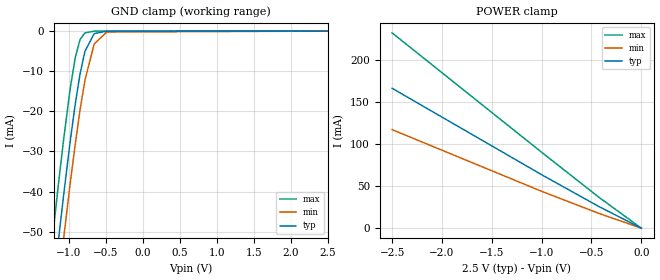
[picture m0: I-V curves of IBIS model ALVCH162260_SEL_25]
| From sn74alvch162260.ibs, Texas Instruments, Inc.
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[Model]   ALVCH162260_SEL_25
Model_type  Input
Vinl=0.7
Vinh=1.7
| variable   typ   min   max
C_comp   27.18pF   21.90pF   32.67pF
[Temperature Range]   40   100   -40
| Ambient temperature   25   85   -40
[Voltage range]   2.5   2.3   2.7
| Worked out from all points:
|   GND clamp passes 1 mA (typ) near -0.68 V on its own axis
|   POWER clamp passes 1 mA (typ) near -0.02 V on its own axis
[GND Clamp]
| ALVCH162260_SEL_25
|   Voltage   I(typ)   I(min)   I(max)
-2.5V     -300mA     -309.4mA   -288.3mA
-1.22V    -65.92mA   -76.78mA   -51.96mA
-1.15V    -54.2mA    -65.07mA   -40.19mA
-1.125V   -50.1mA    -60.96mA   -36.1mA
-1.07V    -41.27mA   -52.08mA   -27.39mA
-980mV    -27.63mA   -38.14mA   -14.46mA
-910mV    -18.08mA   -28.05mA   -6.523mA
-845mV    -10.58mA   -19.54mA   -2.069mA
-780mV    -5.041mA   -12.24mA   -440.8uA
-655mV    -630uA     -3.209mA   -15.41uA
-485mV    -21.18uA   -229.3uA   -148.8nA
2.5V      1.112nA    1.808uA    4.19pA
[POWER Clamp]
| ALVCH162260_SEL_25
|   Voltage   I(typ)   I(min)   I(max)
-2.5V     166mA      116.9mA    231.7mA
-990mV    62.77mA    43.26mA    89.14mA
-425mV    25.67mA    17.51mA    36.62mA
-31.15fV  211.9pA    285.8pA    93.4pA
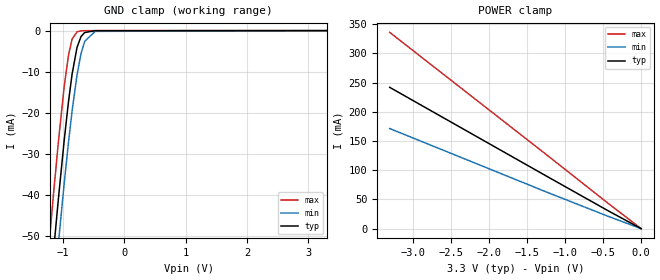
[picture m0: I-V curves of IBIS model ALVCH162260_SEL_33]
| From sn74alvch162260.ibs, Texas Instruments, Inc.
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[Model]   ALVCH162260_SEL_33
Model_type  Input
Vinl=0.8
Vinh=2.0
| variable   typ   min   max
C_comp   28.03pF   21.19pF   32.72pF
[Temperature Range]   40   100   -40
| Ambient temperature   25   85   -40
[Voltage range]   3.3   3   3.6
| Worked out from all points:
|   GND clamp passes 1 mA (typ) near -0.68 V on its own axis
|   POWER clamp passes 1 mA (typ) near -0.01 V on its own axis
[GND Clamp]
| ALVCH162260_SEL_33
|   Voltage   I(typ)   I(min)   I(max)
-3.3V     -451.4mA   -460.2mA   -440.6mA
-1.225V   -66.77mA   -77.63mA   -52.81mA
-1.14V    -52.55mA   -63.42mA   -38.55mA
-1.07V    -41.27mA   -52.08mA   -27.39mA
-975mV    -26.91mA   -37.4mA    -13.81mA
-905mV    -17.45mA   -27.36mA   -6.068mA
-845mV    -10.58mA   -19.54mA   -2.069mA
-765mV    -4.1mA     -10.78mA   -298.6uA
-700mV    -1.444mA   -5.604mA   -52.39uA
-640mV    -472.1uA   -2.617mA   -10.24uA
-470mV    -15.62uA   -178.3uA   -98.79nA
3.3V      1.114nA    9.952uA    5.63pA
[POWER Clamp]
| ALVCH162260_SEL_33
|   Voltage   I(typ)   I(min)   I(max)
-3.3V     241.9mA    171.4mA    336mA
-1.23V    89.02mA    62.04mA    125.3mA
-435mV    30.74mA    21.22mA    43.48mA
-48.03fV  3.196nA    1.217nA    4.97nA
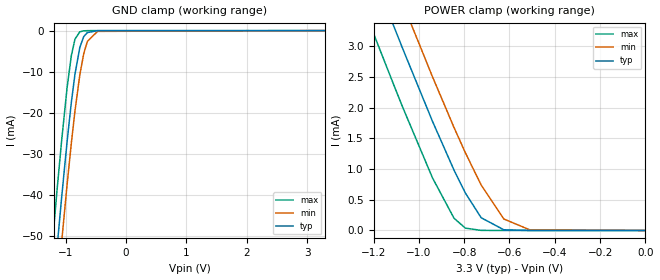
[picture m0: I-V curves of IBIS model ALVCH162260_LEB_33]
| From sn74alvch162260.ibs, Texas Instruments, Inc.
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[Model]   ALVCH162260_LEB_33
Model_type  Input
Vinl=0.8
Vinh=2.0
| variable   typ   min   max
C_comp   1.76pF   1.54pF   2.35pF
[Temperature Range]   40   100   -40
| Ambient temperature   25   85   -40
[Voltage range]   3.3   3   3.6
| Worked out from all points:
|   GND clamp passes 1 mA (typ) near -0.68 V on its own axis
|   POWER clamp passes 1 mA (typ) near -0.85 V on its own axis
[GND Clamp]
| ALVCH162260_LEB_33
|   Voltage   I(typ)   I(min)   I(max)
-3.3V     -451.4mA   -460.2mA   -440.6mA
-1.225V   -66.77mA   -77.63mA   -52.81mA
-1.14V    -52.55mA   -63.42mA   -38.55mA
-1.07V    -41.27mA   -52.08mA   -27.39mA
-975mV    -26.91mA   -37.4mA    -13.81mA
-905mV    -17.45mA   -27.36mA   -6.068mA
-845mV    -10.58mA   -19.54mA   -2.069mA
-765mV    -4.1mA     -10.78mA   -298.6uA
-700mV    -1.444mA   -5.604mA   -52.39uA
-640mV    -472.1uA   -2.617mA   -10.24uA
-470mV    -15.62uA   -178.3uA   -98.79nA
3.3V      1.114nA    9.952uA    5.63pA
[POWER Clamp]
| ALVCH162260_LEB_33
|   Voltage   I(typ)   I(min)   I(max)
-3.3V     24.83mA    25.52mA    23.96mA
-1.275V   4.872mA    5.61mA     3.918mA
-1.185V   4.018mA    4.758mA    3.062mA
-1.105V   3.269mA    4.008mA    2.314mA
-1.07V    2.945mA    3.683mA    1.992mA
-940mV    1.776mA    2.501mA    856.4uA
-845mV    982.9uA    1.676mA    200.1uA
-795mV    611.2uA    1.266mA    38.41uA
-725mV    207uA      738.7uA    1.527uA
-625mV    11.21uA    186.8uA    11.91nA
-510mV    181.6nA    9.688uA    52.91pA
-48.03fV  6.303pA    7.801pA    6.677pA
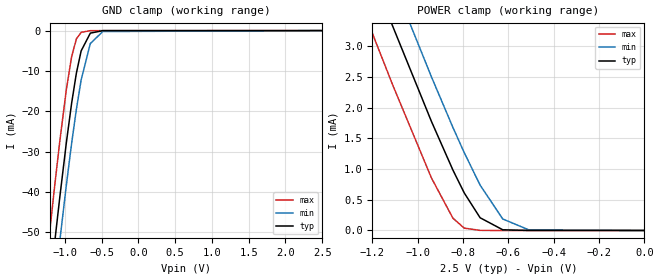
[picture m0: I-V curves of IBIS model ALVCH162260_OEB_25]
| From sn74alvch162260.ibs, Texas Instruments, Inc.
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[Model]   ALVCH162260_OEB_25
Model_type  Input
Vinl=0.7
Vinh=1.7
| variable   typ   min   max
C_comp   1.70pF   1.55pF   2.09pF
[Temperature Range]   40   100   -40
| Ambient temperature   25   85   -40
[Voltage range]   2.5   2.3   2.7
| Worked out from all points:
|   GND clamp passes 1 mA (typ) near -0.68 V on its own axis
|   POWER clamp passes 1 mA (typ) near -0.85 V on its own axis
[GND Clamp]
| ALVCH162260_OEB_25
|   Voltage   I(typ)   I(min)   I(max)
-2.5V     -300mA     -309.4mA   -288.3mA
-1.22V    -65.92mA   -76.78mA   -51.96mA
-1.15V    -54.2mA    -65.07mA   -40.19mA
-1.125V   -50.1mA    -60.96mA   -36.1mA
-1.07V    -41.27mA   -52.08mA   -27.39mA
-980mV    -27.63mA   -38.14mA   -14.46mA
-910mV    -18.08mA   -28.05mA   -6.523mA
-845mV    -10.58mA   -19.54mA   -2.069mA
-780mV    -5.041mA   -12.24mA   -440.8uA
-655mV    -630uA     -3.209mA   -15.41uA
-485mV    -21.18uA   -229.3uA   -148.8nA
2.5V      1.112nA    1.808uA    4.19pA
[POWER Clamp]
| ALVCH162260_OEB_25
|   Voltage   I(typ)   I(min)   I(max)
-2.5V     16.88mA    17.58mA    15.98mA
-1.3V     5.111mA    5.849mA    4.158mA
-1.255V   4.681mA    5.42mA     3.727mA
-1.18V    3.971mA    4.711mA    3.015mA
-1.11V    3.316mA    4.055mA    2.36mA
-940mV    1.776mA    2.501mA    856.4uA
-845mV    982.9uA    1.676mA    200.1uA
-795mV    611.2uA    1.266mA    38.41uA
-725mV    207uA      738.7uA    1.527uA
-625mV    11.21uA    186.8uA    11.91nA
-510mV    181.6nA    9.688uA    51.12pA
-31.15fV  4.712pA    6.41pA     4.886pA
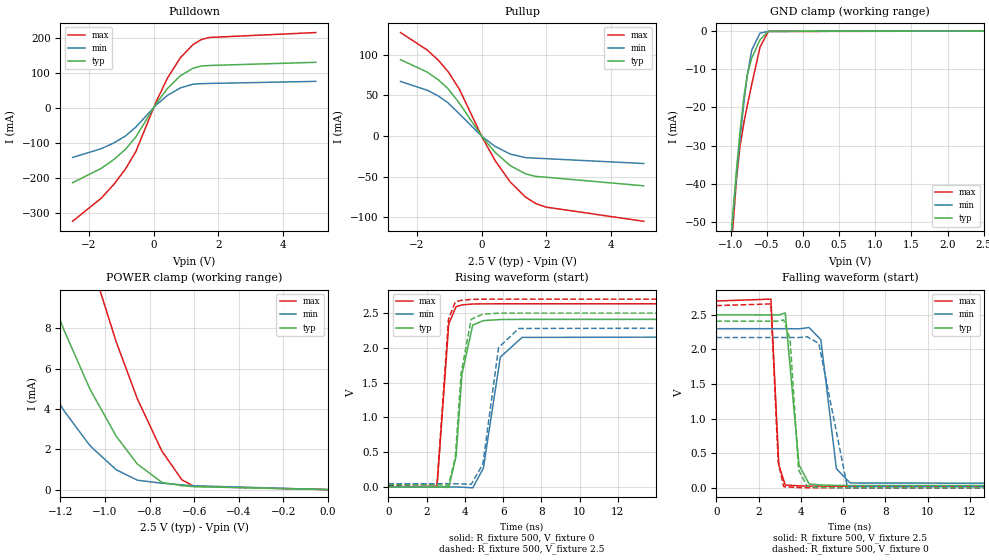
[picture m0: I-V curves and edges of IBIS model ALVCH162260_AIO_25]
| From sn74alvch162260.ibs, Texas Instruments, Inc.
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[Model]   ALVCH162260_AIO_25
Model_type  I/O
Vinl=0.7
Vinh=1.7
Enable   Active-Low
Vref =   0
Rref =   500
Cref =   30p
Vmeas =   1.25
| variable   typ   min   max
C_comp   8.61pF   7.54pF   9.59pF
| C_pullup   9.77pF   8.12pF   10.70pF
| C_pulldown   13.11pF   10.21pF   16.92pF
| C_tri-state   8.61pF   7.54pF   9.59pF
[Temperature Range]   40   100   -40
| Ambient temperature   25   85   -40
[Voltage range]   2.5   2.3   2.7
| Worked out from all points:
|   slope of the pulldown table from 0 to 0.375 V, typ, clamps not added: 7.66 ohm
|   slope of the pullup table from 0 to 0.375 V, typ, clamps not added: 20.6 ohm
|   GND clamp passes 1 mA (typ) near -0.55 V on its own axis
|   POWER clamp passes 1 mA (typ) near -0.83 V on its own axis
|   rising waveform, R_fixture 500, V_fixture 0: 20-80 % time 414ps typ, 652ps min, 290ps max; typ from 0 V to 2.41 V
|   falling waveform, R_fixture 500, V_fixture 2.5: 20-80 % time 280ps typ, 461ps min, 178ps max; typ from 2.5 V to 0.034 V
|   rising waveform, R_fixture 500, V_fixture 2.5: 20-80 % time 397ps typ, 592ps min, 281ps max; typ from 0.034 V to 2.5 V
|   falling waveform, R_fixture 500, V_fixture 0: 20-80 % time 268ps typ, 431ps min, 172ps max; typ from 2.41 V to 0 V
[GND Clamp]
| ALVCH162260_AIO_25
|   Voltage   I(typ)   I(min)   I(max)
-2.5V     -468.2mA   -428.5mA   -529.7mA
-1.095V   -77.4mA    -75.37mA   -83.81mA
-1.08V    -73.67mA   -71.99mA   -79.57mA
-1.06V    -68.73mA   -67.51mA   -73.98mA
-920mV    -36.21mA   -37.68mA   -38.65mA
-870mV    -26.07mA   -27.97mA   -29.9mA
-815mV    -16.78mA   -18.28mA   -23.65mA
-770mV    -11.4mA    -11.53mA   -19.45mA
-710mV    -7.125mA   -5.047mA   -14.04mA
-595mV    -2.318mA   -568.8uA   -4.241mA
-480mV    -118.2uA   -124.4uA   -159.8uA
2.5V      87.96pA    20.8uA     -42.68uA
[POWER Clamp]
| ALVCH162260_AIO_25
|   Voltage   I(typ)   I(min)   I(max)
-2.5V     63.25mA    42.74mA    94.06mA
-1.535V   19.36mA    11.44mA    33.3mA
-1.295V   11.13mA    5.943mA    21.18mA
-1.185V   7.93mA     3.923mA    16.24mA
-1.075V   5.165mA    2.287mA    11.76mA
-1.06V    4.826mA    2.097mA    11.19mA
-950mV    2.649mA    983.8uA    7.329mA
-855mV    1.266mA    465.9uA    4.501mA
-745mV    358.2uA    317uA      1.91mA
-655mV    193uA      236.3uA    483.8uA
-600mV    145.9uA    190.2uA    159.3uA
-31.15fV  87.96pA    322.3pA    50.89pA
[Pulldown]
| ALVCH162260_AIO_25
|   Voltage   I(typ)   I(min)   I(max)
-2.5V     -214.5mA   -142.4mA   -324.7mA
-1.625V   -174.1mA   -117.7mA   -259.4mA
-1.225V   -148.2mA   -100.9mA   -219.1mA
-870mV    -119.2mA   -81.23mA   -175.5mA
-550mV    -84.06mA   -55.7mA    -125.8mA
75mV      10.83mA    7.022mA    16.48mA
430mV     55.09mA    35.04mA    84.84mA
825mV     90.83mA    56.18mA    142.3mA
1.215V    112.2mA    66.71mA    179.9mA
1.465V    118.6mA    68.28mA    193.9mA
1.715V    120.1mA    68.86mA    200.1mA
5V        129.2mA    74.77mA    214.1mA
[Pullup]
| ALVCH162260_AIO_25
|   Voltage   I(typ)   I(min)   I(max)
-2.5V     93.89mA    67.09mA    127.2mA
-1.675V   78.56mA    56.27mA    105.7mA
-1.335V   69.15mA    49.28mA    93.27mA
-1.035V   58.23mA    40.89mA    79.35mA
-685mV    40.38mA    27.22mA    57.59mA
15mV      -812.9uA   -531.7uA   -1.2mA
420mV     -20.15mA   -12.8mA    -30.36mA
885mV     -36.42mA   -22.17mA   -56.52mA
1.355V    -46.47mA   -26.53mA   -75.01mA
1.67V     -49.6mA    -27.19mA   -82.95mA
1.985V    -50.63mA   -27.82mA   -87.32mA
5V        -61.14mA   -33.76mA   -104.8mA
[Ramp]
| ALVCH162260_AIO_25
| variable   typ   min   max
dV/dt_r   1.45/4.21E-10   1.31/6.60E-10   1.59/3.04E-10
dV/dt_f   1.50/2.90E-10   1.37/4.71E-10   1.63/1.89E-10
R_load = 500
[Rising Waveform]
| ALVCH162260_AIO_25
R_fixture =   500
C_fixture =   0
L_fixture =   0
V_fixture =   0
V_fixture_min = 0
V_fixture_max = 0
|   Time   V(typ)   V(min)   V(max)
0s        360.6pV    1.412nV    255.5pV
2.545ns   1.401mV    -88.12uV   11.99mV
3.16ns    -4.821mV   1.034mV    2.347V
3.54ns    440.7mV    703.7uV    2.591V
3.85ns    1.624V     -1.002mV   2.617V
4.415ns   2.327V     -11.56mV   2.63V
4.97ns    2.391V     271.5mV    2.632V
5.855ns   2.407V     1.867V     2.633V
6.995ns   2.409V     2.15V      2.633V
50ns      2.409V     2.172V     2.633V
[Falling Waveform]
| ALVCH162260_AIO_25
R_fixture =   500
C_fixture =   0
L_fixture =   0
V_fixture =   2.5
V_fixture_min = 2.3
V_fixture_max = 2.7
|   Time   V(typ)   V(min)   V(max)
0s        2.5V       2.3V       2.7V
2.585ns   2.499V     2.3V       2.727V
2.96ns    2.498V     2.3V       326.9mV
3.265ns   2.528V     2.3V       40.44mV
3.915ns   331mV      2.298V     29.13mV
4.395ns   55.32mV    2.316V     25.29mV
4.95ns    41.36mV    2.139V     24.37mV
5.685ns   35.35mV    276.9mV    24.06mV
6.33ns    34.11mV    71.3mV     23.99mV
50ns      33.66mV    47.56mV    23.96mV
[Rising Waveform]
| ALVCH162260_AIO_25
R_fixture =   500
C_fixture =   0
L_fixture =   0
V_fixture =   2.5
V_fixture_min = 2.3
V_fixture_max = 2.7
|   Time   V(typ)   V(min)   V(max)
0s        33.65mV    47.56mV    23.96mV
2.545ns   34.63mV    47.55mV    37.19mV
3.145ns   26.99mV    48.28mV    2.411V
3.5ns     423.5mV    47.34mV    2.658V
3.805ns   1.63V      45.73mV    2.683V
4.33ns    2.41V      39.05mV    2.696V
4.94ns    2.484V     327.2mV    2.699V
5.765ns   2.498V     2.005V     2.7V
6.82ns    2.5V       2.278V     2.7V
50ns      2.5V       2.3V       2.7V
[Falling Waveform]
| ALVCH162260_AIO_25
R_fixture =   500
C_fixture =   0
L_fixture =   0
V_fixture =   0
V_fixture_min = 0
V_fixture_max = 0
|   Time   V(typ)   V(min)   V(max)
0s        2.409V     2.172V     2.633V
2.585ns   2.408V     2.172V     2.658V
2.93ns    2.408V     2.173V     377.1mV
3.19ns    2.427V     2.172V     17.32mV
3.495ns   2.143V     2.172V     10.92mV
3.895ns   261mV      2.172V     4.629mV
4.305ns   20.19mV    2.183V     1.361mV
4.855ns   7.087mV    2.086V     399.7uV
6.2ns     389.6uV    19.58mV    34.94uV
50ns      231.3nV    435.8nV    114.6nV
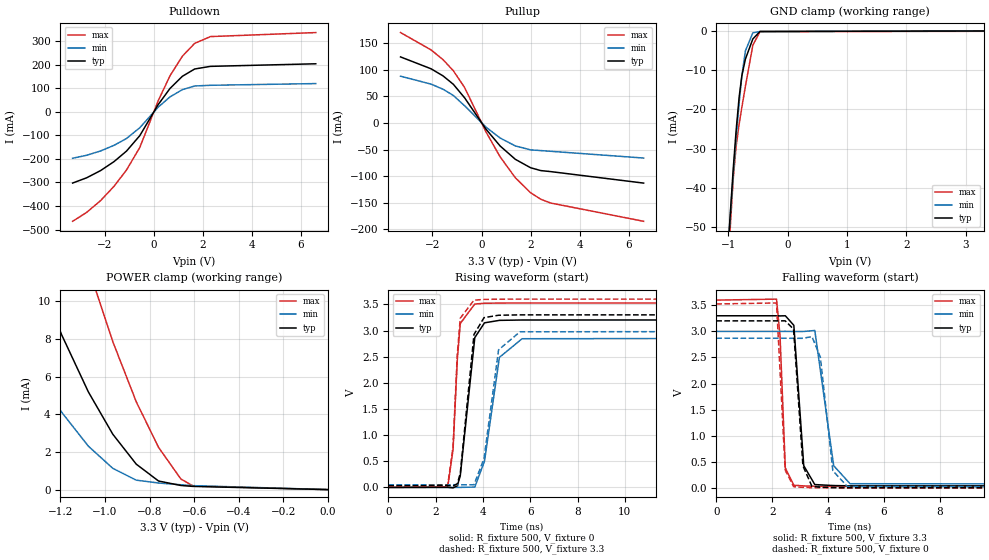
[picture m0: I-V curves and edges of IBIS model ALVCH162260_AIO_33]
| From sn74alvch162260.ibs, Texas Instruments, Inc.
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[Model]   ALVCH162260_AIO_33
Model_type  I/O
Vinl=0.8
Vinh=2.0
Enable   Active-Low
Vref =   0
Rref =   500
Cref =   50p
Vmeas =   1.5
| variable   typ   min   max
C_comp   4.5pF   NA   NA
| C_pullup   9.52pF   7.89pF   10.49pF
| C_pulldown   12.76pF   10.08pF   16.26pF
| C_tri-state   8.39pF   7.23pF   9.52pF
[Temperature Range]   40   100   -40
| Ambient temperature   25   85   -40
[Voltage range]   3.3   3   3.6
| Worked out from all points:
|   slope of the pulldown table from 0 to 0.495 V, typ, clamps not added: 6.36 ohm
|   slope of the pullup table from 0 to 0.495 V, typ, clamps not added: 16.5 ohm
|   GND clamp passes 1 mA (typ) near -0.55 V on its own axis
|   POWER clamp passes 1 mA (typ) near -0.83 V on its own axis
|   rising waveform, R_fixture 500, V_fixture 0: 20-80 % time 343ps typ, 493ps min, 239ps max; typ from 0 V to 3.2 V
|   falling waveform, R_fixture 500, V_fixture 3.3: 20-80 % time 216ps typ, 328ps min, 142ps max; typ from 3.3 V to 0.037 V
|   rising waveform, R_fixture 500, V_fixture 3.3: 20-80 % time 335ps typ, 468ps min, 236ps max; typ from 0.037 V to 3.3 V
|   falling waveform, R_fixture 500, V_fixture 0: 20-80 % time 204ps typ, 312ps min, 139ps max; typ from 3.2 V to 0 V
[GND Clamp]
| ALVCH162260_AIO_33
|   Voltage   I(typ)   I(min)   I(max)
-3.3V     -702.5mA   -640.1mA   -797.1mA
-1.09V    -76.2mA    -74.27mA   -82.45mA
-1.07V    -71.24mA   -69.78mA   -76.83mA
-1.05V    -66.34mA   -65.33mA   -71.28mA
-915mV    -35.19mA   -36.71mA   -37.68mA
-865mV    -25.17mA   -27.07mA   -29.27mA
-815mV    -16.82mA   -18.31mA   -23.7mA
-770mV    -11.44mA   -11.56mA   -19.5mA
-710mV    -7.159mA   -5.072mA   -14.09mA
-585mV    -2.033mA   -471.5uA   -3.632mA
-465mV    -132uA     -129.7uA   -181.2uA
3.3V      119.8pA    41.6uA     -79.23uA
[POWER Clamp]
| ALVCH162260_AIO_33
|   Voltage   I(typ)   I(min)   I(max)
-3.3V     106.7mA    74.61mA    152.6mA
-1.545V   19.78mA    11.73mA    33.9mA
-1.42V    15.27mA    8.669mA    27.34mA
-1.32V    11.95mA    6.481mA    22.41mA
-1.195V   8.24mA     4.119mA    16.72mA
-1.075V   5.198mA    2.312mA    11.8mA
-965mV    2.942mA    1.129mA    7.86mA
-860mV    1.354mA    503uA      4.672mA
-760mV    457.3uA    350.6uA    2.248mA
-660mV    219.9uA    257.6uA    567.3uA
-605mV    170.3uA    210.1uA    193.1uA
-48.03fV  119.8pA    365.6pA    68.2pA
[Pulldown]
| ALVCH162260_AIO_33
|   Voltage   I(typ)   I(min)   I(max)
-3.3V     -302.4mA   -196.9mA   -465.1mA
-2.73V    -280.1mA   -184.3mA   -427.4mA
-2.16V    -249.3mA   -165.8mA   -377mA
-1.61V    -210.9mA   -141.8mA   -315.8mA
-1.105V   -166.3mA   -112.9mA   -246.6mA
-565mV    -100.8mA   -67.07mA   -151.3mA
185mV     31.43mA    20.51mA    47.78mA
665mV     100mA      64.12mA    153.8mA
1.17V     151.9mA    95.01mA    237.4mA
1.67V     182.8mA    110.5mA    291.9mA
2.31V     194mA      113.5mA    320.7mA
6.6V      205mA      120.8mA    337.8mA
[Pullup]
| ALVCH162260_AIO_33
|   Voltage   I(typ)   I(min)   I(max)
-3.3V     124.6mA    88.26mA    170.5mA
-2.055V   102.2mA    73.29mA    137.8mA
-1.565V   88.69mA    63.61mA    119.2mA
-1.15V    73.01mA    51.93mA    98.57mA
-690mV    47.45mA    32.47mA    66.81mA
180mV     -11.59mA   -7.766mA   -16.76mA
755mV     -43.3mA    -28.29mA   -63.76mA
1.375V    -68.47mA   -43.2mA    -103.3mA
1.995V    -84.31mA   -50.62mA   -131.4mA
2.405V    -89.66mA   -51.96mA   -143.6mA
2.81V     -91.58mA   -53.32mA   -150.8mA
6.6V      -113.3mA   -66.05mA   -185.3mA
[Ramp]
| ALVCH162260_AIO_33
| variable   typ   min   max
dV/dt_r   1.93/3.53E-10   1.73/5.04E-10   2.12/2.40E-10
dV/dt_f   1.98/2.23E-10   1.79/3.39E-10   2.16/1.46E-10
R_load = 500
[Rising Waveform]
| ALVCH162260_AIO_33
R_fixture =   500
C_fixture =   0
L_fixture =   0
V_fixture =   0
V_fixture_min = 0
V_fixture_max = 0
|   Time   V(typ)   V(min)   V(max)
0s        395.9pV    1.295nV    284.2pV
2.51ns    2.238mV    69uV       12.47mV
2.735ns   -7.841mV   1.226mV    723.5mV
2.915ns   30.69mV    1.806mV    2.441V
3.04ns    221mV      1.18mV     3.134V
3.655ns   2.865V     7.182mV    3.506V
4.065ns   3.147V     499.9mV    3.521V
4.695ns   3.194V     2.487V     3.525V
5.655ns   3.201V     2.843V     3.526V
50ns      3.202V     2.869V     3.526V
[Falling Waveform]
| ALVCH162260_AIO_33
R_fixture =   500
C_fixture =   0
L_fixture =   0
V_fixture =   3.3
V_fixture_min = 3
V_fixture_max = 3.6
|   Time   V(typ)   V(min)   V(max)
0s        3.3V       3V         3.6V
2.155ns   3.3V       3V         3.619V
2.28ns    3.297V     3V         2.925V
2.47ns    3.3V       3.001V     382.4mV
2.775ns   3.117V     2.998V     50.91mV
3.13ns    425mV      2.999V     37.26mV
3.525ns   63.14mV    3.018V     29.87mV
4.2ns     44.17mV    425.6mV    27.32mV
4.785ns   38.61mV    79.66mV    26.89mV
50ns      37.01mV    51.2mV     26.69mV
[Rising Waveform]
| ALVCH162260_AIO_33
R_fixture =   500
C_fixture =   0
L_fixture =   0
V_fixture =   3.3
V_fixture_min = 3
V_fixture_max = 3.6
|   Time   V(typ)   V(min)   V(max)
0s        37.01mV    51.2mV     26.69mV
2.51ns    38.7mV     51.35mV    40.04mV
2.735ns   28.75mV    52.26mV    781.9mV
2.915ns   69.82mV    52.38mV    2.544V
3.04ns    267.3mV    51.42mV    3.236V
3.62ns    2.924V     51.11mV    3.58V
4.045ns   3.246V     553.5mV    3.595V
4.66ns    3.292V     2.63V      3.599V
5.565ns   3.299V     2.975V     3.6V
50ns      3.3V       3V         3.6V
[Falling Waveform]
| ALVCH162260_AIO_33
R_fixture =   500
C_fixture =   0
L_fixture =   0
V_fixture =   0
V_fixture_min = 0
V_fixture_max = 0
|   Time   V(typ)   V(min)   V(max)
0s        3.202V     2.869V     3.526V
2.155ns   3.202V     2.869V     3.545V
2.465ns   3.203V     2.869V     340.7mV
2.765ns   3.044V     2.867V     22.43mV
3.1ns     422mV      2.868V     10.2mV
3.425ns   25.36mV    2.9V       3.796mV
3.725ns   14.88mV    2.505V     1.536mV
4.17ns    6.313mV    328.1mV    578uV
4.69ns    1.564mV    25.95mV    207.8uV
50ns      175.1nV    317.2nV    87.06nV
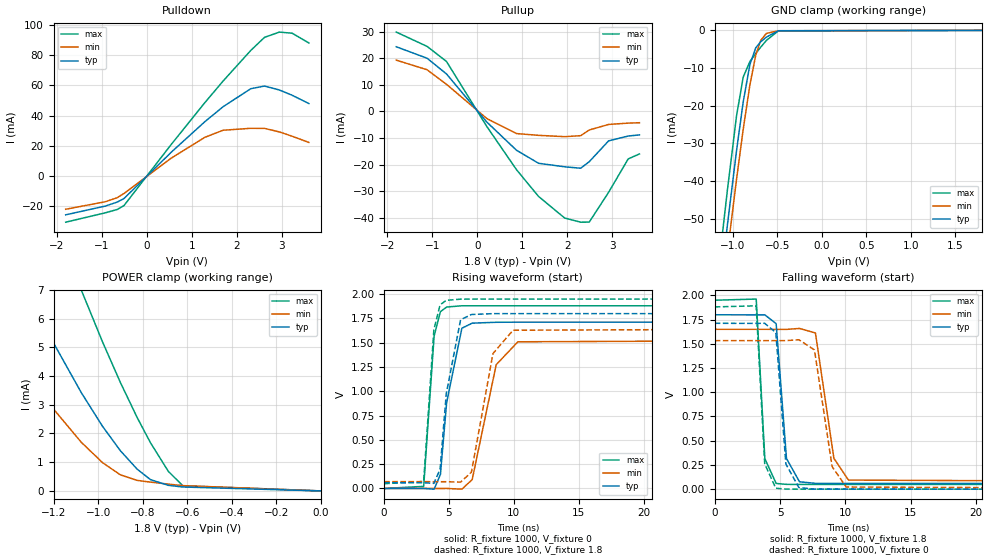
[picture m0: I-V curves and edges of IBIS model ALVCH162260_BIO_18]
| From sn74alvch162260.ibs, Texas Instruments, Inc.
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[Model]   ALVCH162260_BIO_18
Model_type  I/O
Vinl=0.5775
Vinh=1.2675
Enable   Active-Low
Vref =   0
Rref =   1000
Cref =   30p
Vmeas =   0.9
| variable   typ   min   max
C_comp   8.99pF   7.67pF   9.87pF
| C_pullup   8.04pF   5.96pF   10.23pF
| C_pulldown   6.53pF   5.66pF   7.39pF
| C_tri-state   8.99pF   7.67pF   9.87pF
[Temperature Range]   40   100   -40
| Ambient temperature   25   85   -40
[Voltage range]   1.8   1.65   1.95
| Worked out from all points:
|   slope of the pulldown table from 0 to 0.27 V, typ, clamps not added: 34.2 ohm
|   slope of the pullup table from 0 to 0.27 V, typ, clamps not added: 53.3 ohm
|   GND clamp passes 1 mA (typ) near -0.57 V on its own axis
|   POWER clamp passes 1 mA (typ) near -0.86 V on its own axis
|   rising waveform, R_fixture 1000, V_fixture 0: 20-80 % time 748ps typ, 1.38ns min, 480ps max; typ from 0 V to 1.71 V
|   falling waveform, R_fixture 1000, V_fixture 1.8: 20-80 % time 535ps typ, 901ps min, 353ps max; typ from 1.8 V to 0.059 V
|   rising waveform, R_fixture 1000, V_fixture 1.8: 20-80 % time 710ps typ, 1.22ns min, 469ps max; typ from 0.059 V to 1.8 V
|   falling waveform, R_fixture 1000, V_fixture 0: 20-80 % time 527ps typ, 901ps min, 350ps max; typ from 1.71 V to 0 V
[GND Clamp]
| ALVCH162260_BIO_18
|   Voltage   I(typ)   I(min)   I(max)
-1.8V     -210.5mA   -213.3mA   -208.1mA
-1.145V   -69.35mA   -76.29mA   -60.75mA
-1.105V   -61.16mA   -68.31mA   -52.23mA
-1.06V    -52.1mA    -59.46mA   -42.85mA
-955mV    -31.87mA   -39.5mA    -22.66mA
-880mV    -18.94mA   -26.2mA    -12.37mA
-805mV    -9.029mA   -14.43mA   -8.258mA
-740mV    -4.65mA    -6.61mA    -6.135mA
-685mV    -3.043mA   -2.694mA   -4.475mA
-620mV    -1.783mA   -796.2uA   -2.665mA
-485mV    -96.67uA   -107.2uA   -131.7uA
1.8V      62.04pA    9.524uA    -22.72uA
[POWER Clamp]
| ALVCH162260_BIO_18
|   Voltage   I(typ)   I(min)   I(max)
-1.8V     15.34mA    10.39mA    23.37mA
-1.545V   10.74mA    6.906mA    17.22mA
-1.32V    6.986mA    4.147mA    12.09mA
-1.195V   5.081mA    2.802mA    9.414mA
-1.075V   3.416mA    1.69mA     6.984mA
-980mV    2.247mA    984.2uA    5.185mA
-900mV    1.399mA    559.2uA    3.774mA
-825mV    758.5uA    366.9uA    2.558mA
-765mV    392.7uA    307.1uA    1.677mA
-685mV    194.7uA    237.1uA    681.5uA
-620mV    136.7uA    184.3uA    179.7uA
-16.28fV  62.04pA    283.7pA    35.23pA
[Pulldown]
| ALVCH162260_BIO_18
|   Voltage   I(typ)   I(min)   I(max)
-1.8V     -25.65mA   -21.98mA   -30.53mA
-920mV    -19.87mA   -17.01mA   -24.33mA
-655mV    -17.23mA   -14.32mA   -22.12mA
-505mV    -14.88mA   -11.53mA   -19.53mA
550mV     15.9mA     11.93mA    21.11mA
1.29V     35.91mA    25.58mA    48.49mA
1.695V    45.8mA     30.26mA    62.78mA
2.31V     57.72mA    31.54mA    83.02mA
2.615V    59.47mA    31.49mA    91.67mA
2.945V    56.88mA    29.16mA    95.15mA
3.23V     53.37mA    26.28mA    94.4mA
3.6V      47.9mA     22.21mA    87.95mA
[Pullup]
| ALVCH162260_BIO_18
|   Voltage   I(typ)   I(min)   I(max)
-1.8V     24.29mA    19.27mA    29.81mA
-1.115V   19.98mA    15.66mA    24.43mA
-685mV    14.08mA    10.2mA     18.77mA
210mV     -3.976mA   -2.661mA   -5.642mA
870mV     -14.59mA   -8.321mA   -21.89mA
1.36V     -19.48mA   -8.981mA   -31.95mA
1.94V     -20.8mA    -9.48mA    -40.05mA
2.295V    -21.34mA   -9.103mA   -41.61mA
2.485V    -18.89mA   -6.958mA   -41.58mA
2.915V    -11.06mA   -4.89mA    -30.39mA
3.35V     -9.248mA   -4.39mA    -17.84mA
3.6V      -8.807mA   -4.241mA   -15.97mA
[Ramp]
| ALVCH162260_BIO_18
| variable   typ   min   max
dV/dt_r   1.03/7.53E-10   0.92/1.38E-09   1.13/4.90E-10
dV/dt_f   1.06/5.45E-10   0.97/9.23E-10   1.15/3.62E-10
R_load = 1000
[Rising Waveform]
| ALVCH162260_BIO_18
R_fixture =   1000
C_fixture =   0
L_fixture =   0
V_fixture =   0
V_fixture_min = 0
V_fixture_max = 0
|   Time   V(typ)   V(min)   V(max)
0s        407pV      1.839nV    289.8pV
3.05ns    241.9uV    589.6uV    21.95mV
3.855ns   -7.095mV   185uV      1.57V
4.34ns    144.2mV    44.14uV    1.82V
4.82ns    883mV      250.1uV    1.868V
5.995ns   1.65V      -7.005mV   1.881V
6.79ns    1.702V     91.35mV    1.881V
8.64ns    1.711V     1.274V     1.881V
10.31ns   1.712V     1.51V      1.881V
50ns      1.712V     1.533V     1.881V
[Falling Waveform]
| ALVCH162260_BIO_18
R_fixture =   1000
C_fixture =   0
L_fixture =   0
V_fixture =   1.8
V_fixture_min = 1.65
V_fixture_max = 1.95
|   Time   V(typ)   V(min)   V(max)
0s        1.8V       1.65V      1.95V
3.175ns   1.799V     1.65V      1.962V
3.835ns   1.799V     1.65V      315mV
4.7ns     1.708V     1.649V     58.96mV
5.49ns    316.6mV    1.649V     49.63mV
6.485ns   76.36mV    1.659V     48.88mV
7.705ns   59.92mV    1.612V     48.76mV
9.115ns   59.03mV    318.9mV    48.74mV
10.23ns   58.95mV    93.81mV    48.73mV
50ns      58.91mV    70.13mV    48.73mV
[Rising Waveform]
| ALVCH162260_BIO_18
R_fixture =   1000
C_fixture =   0
L_fixture =   0
V_fixture =   1.8
V_fixture_min = 1.65
V_fixture_max = 1.95
|   Time   V(typ)   V(min)   V(max)
0s        58.91mV    70.13mV    48.73mV
3.05ns    58.68mV    70.59mV    72.46mV
3.835ns   52.76mV    69.63mV    1.634V
4.315ns   198.1mV    69.39mV    1.891V
4.79ns    974.3mV    69.55mV    1.937V
5.895ns   1.737V     65.48mV    1.949V
6.73ns    1.791V     167.5mV    1.95V
8.39ns    1.8V       1.389V     1.95V
9.935ns   1.8V       1.629V     1.95V
50ns      1.8V       1.65V      1.95V
[Falling Waveform]
| ALVCH162260_BIO_18
R_fixture =   1000
C_fixture =   0
L_fixture =   0
V_fixture =   0
V_fixture_min = 0
V_fixture_max = 0
|   Time   V(typ)   V(min)   V(max)
0s        1.712V     1.533V     1.881V
3.17ns    1.711V     1.533V     1.892V
3.825ns   1.712V     1.533V     261.1mV
4.675ns   1.616V     1.533V     9.642mV
5.445ns   259.7mV    1.533V     830.8uV
6.44ns    16.06mV    1.542V     141.6uV
7.63ns    804uV      1.437V     28.89uV
8.98ns    100.1uV    233.1mV    9.534uV
10.06ns   33.86uV    22.07mV    5.833uV
50ns      1.314uV    2.151uV    710.4nV
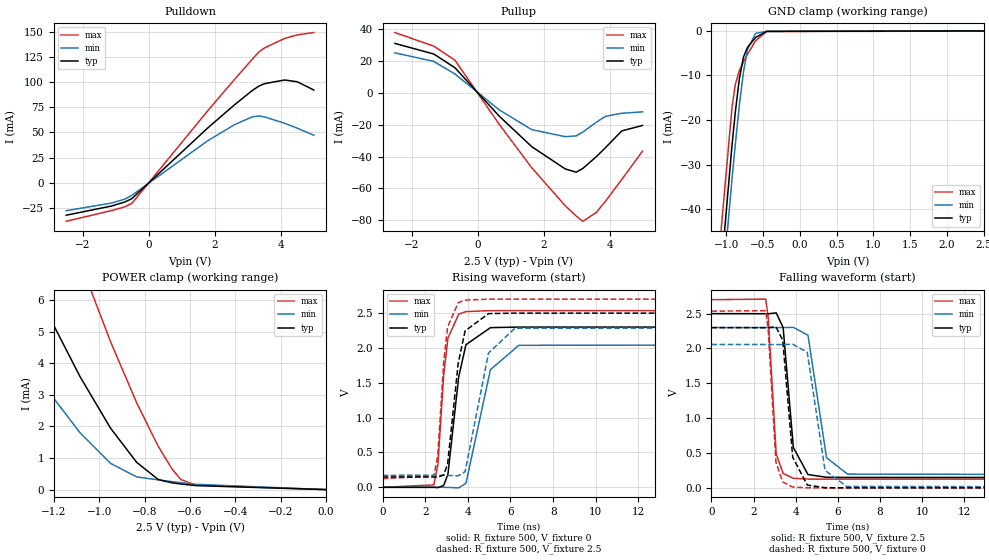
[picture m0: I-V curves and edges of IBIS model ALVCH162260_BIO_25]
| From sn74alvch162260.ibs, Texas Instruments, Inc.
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[Model]   ALVCH162260_BIO_25
Model_type  I/O
Vinl=0.7
Vinh=1.7
Enable   Active-Low
Vref =   0
Rref =   500
Cref =   30p
Vmeas =   1.25
| variable   typ   min   max
C_comp   8.76pF   7.25pF   9.79pF
| C_pullup   7.04pF   5.41pF   9.87pF
| C_pulldown   6.00pF   5.18pF   6.94pF
| C_tri-state   8.76pF   7.25pF   9.79pF
[Temperature Range]   40   100   -40
| Ambient temperature   25   85   -40
[Voltage range]   2.5   2.3   2.7
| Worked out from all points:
|   slope of the pulldown table from 0 to 0.375 V, typ, clamps not added: 32 ohm
|   slope of the pullup table from 0 to 0.375 V, typ, clamps not added: 44.3 ohm
|   GND clamp passes 1 mA (typ) near -0.57 V on its own axis
|   POWER clamp passes 1 mA (typ) near -0.85 V on its own axis
|   rising waveform, R_fixture 500, V_fixture 0: 20-80 % time 515ps typ, 742ps min, 364ps max; typ from 0 V to 2.3 V
|   falling waveform, R_fixture 500, V_fixture 2.5: 20-80 % time 378ps typ, 546ps min, 264ps max; typ from 2.5 V to 0.149 V
|   rising waveform, R_fixture 500, V_fixture 2.5: 20-80 % time 497ps typ, 685ps min, 357ps max; typ from 0.149 V to 2.5 V
|   falling waveform, R_fixture 500, V_fixture 0: 20-80 % time 373ps typ, 525ps min, 263ps max; typ from 2.3 V to 0 V
[GND Clamp]
| ALVCH162260_BIO_25
|   Voltage   I(typ)   I(min)   I(max)
-2.5V     -366.4mA   -364.8mA   -370.3mA
-1.15V    -70.43mA   -77.33mA   -61.89mA
-1.115V   -63.25mA   -70.34mA   -54.41mA
-1.07V    -54.15mA   -61.46mA   -44.98mA
-920mV    -25.65mA   -33.19mA   -17.16mA
-875mV    -18.2mA    -25.39mA   -11.99mA
-820mV    -10.68mA   -16.64mA   -8.87mA
-765mV    -5.913mA   -9.29mA    -6.974mA
-710mV    -3.695mA   -4.173mA   -5.266mA
-600mV    -1.477mA   -551.2uA   -2.198mA
-450mV    -100.1uA   -100.7uA   -139.6uA
2.5V      85.81pA    20.8uA     -42.68uA
[POWER Clamp]
| ALVCH162260_BIO_25
|   Voltage   I(typ)   I(min)   I(max)
-2.5V     29.26mA    21.19mA    41.6mA
-1.575V   11.31mA    7.339mA    17.99mA
-1.33V    7.189mA    4.297mA    12.37mA
-1.205V   5.269mA    2.936mA    9.674mA
-1.085V   3.585mA    1.805mA    7.228mA
-950mV    1.946mA    830.8uA    4.685mA
-835mV    864.4uA    402.7uA    2.751mA
-740mV    319.6uA    307uA      1.374mA
-680mV    215.8uA    254.1uA    662.1uA
-640mV    178uA      220.3uA    318.1uA
-575mV    127.2uA    168uA      143uA
-31.15fV  85.81pA    320.1pA    48.77pA
[Pulldown]
| ALVCH162260_BIO_25
|   Voltage   I(typ)   I(min)   I(max)
-2.5V     -32.43mA   -27.95mA   -38.48mA
-1.125V   -23.26mA   -20.28mA   -27.77mA
-730mV    -19.32mA   -16.51mA   -24.2mA
-510mV    -15.9mA    -12.59mA   -20.61mA
1.78V     54.23mA    41.53mA    71.26mA
2.59V     77.25mA    57.56mA    102.4mA
3.14V     91.8mA     65.55mA    123mA
3.335V    96.06mA    66.38mA    130mA
3.505V    98.5mA     65.47mA    134.1mA
4.12V     102.2mA    59.07mA    143.6mA
4.5V      100.4mA    54.17mA    147.1mA
5V        92.22mA    47.22mA    149.4mA
[Pullup]
| ALVCH162260_BIO_25
|   Voltage   I(typ)   I(min)   I(max)
-2.5V     31.21mA    25.25mA    38.05mA
-1.325V   24.54mA    19.91mA    29.49mA
-685mV    15.91mA    11.97mA    20.69mA
660mV     -14.63mA   -10.67mA   -19.8mA
1.645V    -33.85mA   -23.09mA   -47.11mA
2.66V     -47.85mA   -27.51mA   -71.08mA
2.99V     -49.86mA   -26.98mA   -77.46mA
3.19V     -47.5mA    -24.61mA   -80.79mA
3.595V    -40.18mA   -18.46mA   -75.27mA
3.875V    -34.45mA   -14.7mA    -68.21mA
4.37V     -23.87mA   -12.76mA   -54.45mA
5V        -20.43mA   -11.88mA   -36.56mA
[Ramp]
| ALVCH162260_BIO_25
| variable   typ   min   max
dV/dt_r   1.38/5.24E-10   1.24/7.48E-10   1.52/3.71E-10
dV/dt_f   1.42/3.88E-10   1.29/5.56E-10   1.56/2.70E-10
R_load = 500
[Rising Waveform]
| ALVCH162260_BIO_25
R_fixture =   500
C_fixture =   0
L_fixture =   0
V_fixture =   0
V_fixture_min = 0
V_fixture_max = 0
|   Time   V(typ)   V(min)   V(max)
0s        436.9pV    1.484nV    320.7pV
2.4ns     -273.9uV   953uV      34.5mV
2.595ns   -4.131mV   1.226mV    326.8mV
2.865ns   26.53mV    168uV      1.609V
3.065ns   188.1mV    -1.376mV   2.141V
3.57ns    1.585V     -7.711mV   2.484V
3.91ns    2.046V     57.7mV     2.521V
5.06ns    2.291V     1.688V     2.535V
6.39ns    2.299V     2.037V     2.535V
50ns      2.299V     2.057V     2.535V
[Falling Waveform]
| ALVCH162260_BIO_25
R_fixture =   500
C_fixture =   0
L_fixture =   0
V_fixture =   2.5
V_fixture_min = 2.3
V_fixture_max = 2.7
|   Time   V(typ)   V(min)   V(max)
0s        2.5V       2.3V       2.7V
2.58ns    2.499V     2.3V       2.708V
2.7ns     2.498V     2.3V       2.434V
3.075ns   2.511V     2.299V     486.6mV
3.405ns   2.301V     2.299V     207mV
3.89ns    579.9mV    2.303V     137mV
4.585ns   190.8mV    2.19V      126.5mV
5.465ns   152mV      432.7mV    125.6mV
6.465ns   149.4mV    197.5mV    125.5mV
50ns      149mV      172.1mV    125.4mV
[Rising Waveform]
| ALVCH162260_BIO_25
R_fixture =   500
C_fixture =   0
L_fixture =   0
V_fixture =   2.5
V_fixture_min = 2.3
V_fixture_max = 2.7
|   Time   V(typ)   V(min)   V(max)
0s        149mV      172.1mV    125.4mV
2.4ns     148.1mV    172.8mV    161.9mV
2.59ns    144.6mV    172.7mV    458.3mV
2.86ns    176.8mV    171.2mV    1.78V
3.05ns    334.8mV    169.7mV    2.299V
3.545ns   1.776V     165.1mV    2.65V
3.87ns    2.244V     224.3mV    2.686V
4.97ns    2.492V     1.928V     2.699V
6.205ns   2.499V     2.281V     2.7V
50ns      2.5V       2.3V       2.7V
[Falling Waveform]
| ALVCH162260_BIO_25
R_fixture =   500
C_fixture =   0
L_fixture =   0
V_fixture =   0
V_fixture_min = 0
V_fixture_max = 0
|   Time   V(typ)   V(min)   V(max)
0s        2.299V     2.057V     2.535V
2.58ns    2.298V     2.057V     2.542V
2.695ns   2.298V     2.057V     2.275V
3.065ns   2.31V      2.056V     363.3mV
3.385ns   2.12V      2.057V     85.33mV
3.86ns    438.8mV    2.061V     11.23mV
4.55ns    40.49mV    1.945V     1.008mV
5.395ns   2.633mV    250.6mV    221.8uV
6.42ns    328.8uV    20.39mV    53.03uV
50ns      1.056uV    1.608uV    616.6nV
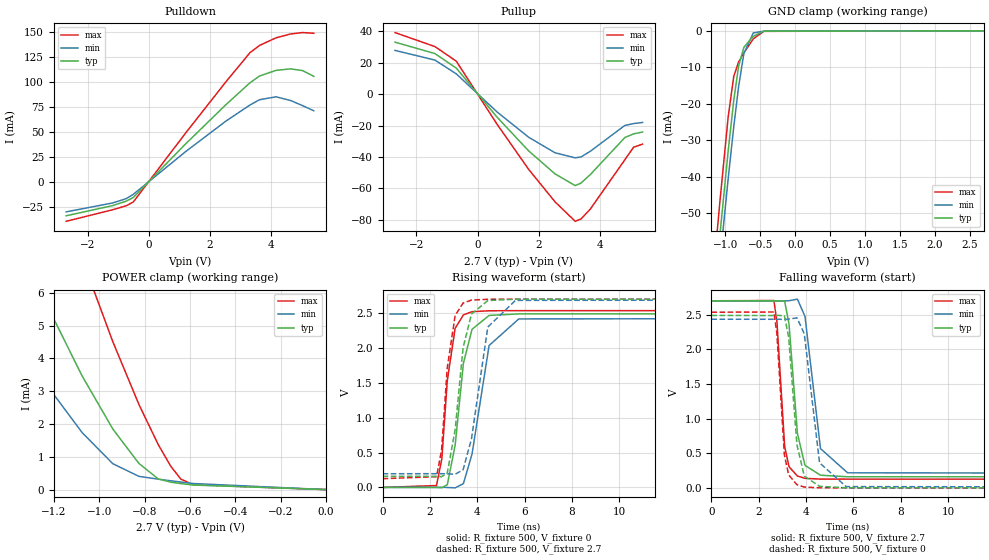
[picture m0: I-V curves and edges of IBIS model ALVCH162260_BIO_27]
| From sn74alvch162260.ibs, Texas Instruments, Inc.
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[Model]   ALVCH162260_BIO_27
Model_type  I/O
Vinl=0.8
Vinh=2.0
Enable   Active-Low
Vref =   0
Rref =   500
Cref =   50p
Vmeas =   1.5
| variable   typ   min   max
C_comp   8.69pF   7.13pF   9.78pF
| C_pullup   6.81pF   5.25pF   9.11pF
| C_pulldown   5.90pF   5.05pF   6.93pF
| C_tri-state   8.69pF   7.13pF   9.78pF
[Temperature Range]   40   100   -40
| Ambient temperature   25   85   -40
[Voltage range]   2.7   2.7   2.7
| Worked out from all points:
|   slope of the pulldown table from 0 to 0.405 V, typ, clamps not added: 31.6 ohm
|   slope of the pullup table from 0 to 0.405 V, typ, clamps not added: 43.1 ohm
|   GND clamp passes 1 mA (typ) near -0.57 V on its own axis
|   POWER clamp passes 1 mA (typ) near -0.85 V on its own axis
|   rising waveform, R_fixture 500, V_fixture 0: 20-80 % time 490ps typ, 637ps min, 367ps max; typ from 0 V to 2.49 V
|   falling waveform, R_fixture 500, V_fixture 2.7: 20-80 % time 359ps typ, 466ps min, 270ps max; typ from 2.7 V to 0.159 V
|   rising waveform, R_fixture 500, V_fixture 2.7: 20-80 % time 476ps typ, 606ps min, 360ps max; typ from 0.159 V to 2.7 V
|   falling waveform, R_fixture 500, V_fixture 0: 20-80 % time 356ps typ, 455ps min, 270ps max; typ from 2.49 V to 0 V
[GND Clamp]
| ALVCH162260_BIO_27
|   Voltage   I(typ)   I(min)   I(max)
-2.7V     -411.3mA   -408.4mA   -417mA
-1.19V    -78.74mA   -85.42mA   -70.55mA
-1.15V    -70.45mA   -77.35mA   -61.89mA
-1.115V   -63.27mA   -70.36mA   -54.41mA
-1.08V    -56.17mA   -63.44mA   -47.05mA
-960mV    -32.85mA   -40.48mA   -23.58mA
-880mV    -19mA      -26.25mA   -12.43mA
-810mV    -9.592mA   -15.19mA   -8.492mA
-735mV    -4.503mA   -6.189mA   -6.03mA
-600mV    -1.485mA   -564.2uA   -2.198mA
-450mV    -106.4uA   -110.8uA   -139.6uA
2.7V      93.14pA    343.9pA    48.77pA
[POWER Clamp]
| ALVCH162260_BIO_27
|   Voltage   I(typ)   I(min)   I(max)
-2.7V     33.46mA    24.49mA    47.02mA
-1.55V    10.89mA    7.031mA    17.4mA
-1.325V   7.121mA    4.258mA    12.26mA
-1.195V   5.132mA    2.851mA    9.465mA
-1.075V   3.462mA    1.736mA    7.031mA
-940mV    1.847mA    789.4uA    4.508mA
-825mV    796.4uA    403.9uA    2.595mA
-740mV    326.3uA    318.3uA    1.374mA
-685mV    227.3uA    268.9uA    714.2uA
-640mV    183.9uA    230.3uA    318.1uA
-585mV    139.7uA    185.1uA    148.7uA
-35.59fV  93.15pA    343.9pA    48.77pA
[Pulldown]
| ALVCH162260_BIO_27
|   Voltage   I(typ)   I(min)   I(max)
-2.7V     -34.28mA   -30.37mA   -39.83mA
-1.18V    -24.09mA   -21.44mA   -28.26mA
-745mV    -19.75mA   -17.2mA    -24.36mA
-510mV    -16.07mA   -12.94mA   -20.61mA
1.205V    37.69mA    30mA       48.59mA
2.53V     77.23mA    60.73mA    100.2mA
3.315V    99.11mA    76.83mA    129.3mA
3.63V     105.9mA    82.12mA    136.6mA
4.165V    111.5mA    84.98mA    144.1mA
4.64V     113mA      81.3mA     148mA
5.035V    111.3mA    76.12mA    149.4mA
5.4V      105.5mA    70.98mA    148.7mA
[Pullup]
| ALVCH162260_BIO_27
|   Voltage   I(typ)   I(min)   I(max)
-2.7V     32.98mA    27.74mA    39.07mA
-1.395V   25.74mA    21.6mA     30.17mA
-695mV    16.5mA     12.84mA    20.9mA
640mV     -14.68mA   -11.37mA   -19.21mA
1.675V    -36.15mA   -27.45mA   -47.89mA
2.535V    -50.7mA    -37.3mA    -68.45mA
3.195V    -58.16mA   -40.52mA   -80.84mA
3.385V    -56.54mA   -39.96mA   -79.37mA
3.69V     -51.16mA   -36.35mA   -73.07mA
4.82V     -27.64mA   -19.94mA   -41.74mA
5.105V    -25.29mA   -18.76mA   -33.8mA
5.4V      -24.13mA   -18.04mA   -31.8mA
[Ramp]
| ALVCH162260_BIO_27
| variable   typ   min   max
dV/dt_r   1.50/4.96E-10   1.46/6.43E-10   1.52/3.71E-10
dV/dt_f   1.53/3.71E-10   1.52/4.73E-10   1.55/2.79E-10
R_load = 500
[Rising Waveform]
| ALVCH162260_BIO_27
R_fixture =   500
C_fixture =   0
L_fixture =   0
V_fixture =   0
V_fixture_min = 0
V_fixture_max = 0
|   Time   V(typ)   V(min)   V(max)
0s        451.2pV    1.421nV    320.7pV
2.275ns   140.7uV    877.8uV    26.79mV
2.5ns     -5.159mV   1.508mV    401.9mV
2.735ns   40.28mV    -815.6uV   1.538V
3.065ns   605.1mV    -6.247mV   2.281V
3.415ns   1.782V     54.7mV     2.474V
3.78ns    2.268V     480.9mV    2.52V
4.5ns     2.466V     2.035V     2.533V
5.755ns   2.488V     2.416V     2.535V
50ns      2.489V     2.434V     2.535V
[Falling Waveform]
| ALVCH162260_BIO_27
R_fixture =   500
C_fixture =   0
L_fixture =   0
V_fixture =   2.7
V_fixture_min = 2.7
V_fixture_max = 2.7
|   Time   V(typ)   V(min)   V(max)
0s        2.7V       2.7V       2.7V
2.64ns    2.698V     2.699V     2.704V
2.77ns    2.7V       2.699V     2.392V
3.095ns   2.694V     2.698V     598mV
3.28ns    2.365V     2.701V     304.6mV
3.635ns   783.2mV    2.724V     170.7mV
3.955ns   324.2mV    2.474V     137.1mV
4.61ns    182.7mV    566.7mV    126.6mV
5.755ns   160.1mV    217.3mV    125.6mV
50ns      159.2mV    196.2mV    125.4mV
[Rising Waveform]
| ALVCH162260_BIO_27
R_fixture =   500
C_fixture =   0
L_fixture =   0
V_fixture =   2.7
V_fixture_min = 2.7
V_fixture_max = 2.7
|   Time   V(typ)   V(min)   V(max)
0s        159.2mV    196.2mV    125.4mV
2.275ns   158.8mV    197mV      153.8mV
2.49ns    154mV      197.2mV    526.3mV
2.73ns    200.4mV    194.5mV    1.712V
3.065ns   828.9mV    189.7mV    2.465V
3.4ns     2V         251.5mV    2.643V
3.755ns   2.487V     696.2mV    2.686V
4.445ns   2.679V     2.299V     2.698V
5.615ns   2.699V     2.682V     2.7V
50ns      2.7V       2.7V       2.7V
[Falling Waveform]
| ALVCH162260_BIO_27
R_fixture =   500
C_fixture =   0
L_fixture =   0
V_fixture =   0
V_fixture_min = 0
V_fixture_max = 0
|   Time   V(typ)   V(min)   V(max)
0s        2.489V     2.434V     2.535V
2.64ns    2.487V     2.433V     2.538V
2.765ns   2.49V      2.433V     2.232V
3.085ns   2.484V     2.433V     474.5mV
3.265ns   2.173V     2.436V     186.7mV
3.615ns   621.1mV    2.454V     45.1mV
3.925ns   170.7mV    2.224V     11.35mV
4.57ns    22.06mV    361.1mV    1.117mV
5.695ns   814.9uV    18.06mV    154.2uV
50ns      1.015uV    1.454uV    617.5nV
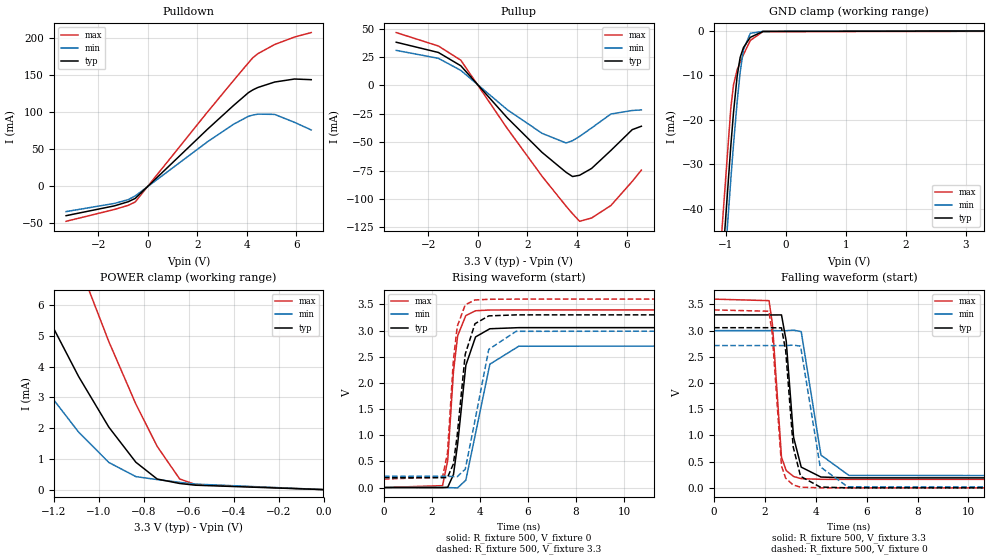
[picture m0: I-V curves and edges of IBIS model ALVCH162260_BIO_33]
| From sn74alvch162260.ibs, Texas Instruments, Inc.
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[Model]   ALVCH162260_BIO_33
Model_type  I/O
Vinl=0.8
Vinh=2.0
Enable   Active-Low
Vref =   0
Rref =   500
Cref =   50p
Vmeas =   1.5
| variable   typ   min   max
C_comp   4.5pF   NA   NA
| C_pullup   6.45pF   5.04pF   8.71pF
| C_pulldown   5.76pF   4.83pF   6.94pF
| C_tri-state   8.53pF   7.02pF   9.78pF
[Temperature Range]   40   100   -40
| Ambient temperature   25   85   -40
[Voltage range]   3.3   3   3.6
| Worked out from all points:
|   slope of the pulldown table from 0 to 0.495 V, typ, clamps not added: 30.8 ohm
|   slope of the pullup table from 0 to 0.495 V, typ, clamps not added: 40.6 ohm
|   GND clamp passes 1 mA (typ) near -0.57 V on its own axis
|   POWER clamp passes 1 mA (typ) near -0.85 V on its own axis
|   rising waveform, R_fixture 500, V_fixture 0: 20-80 % time 433ps typ, 593ps min, 321ps max; typ from 0 V to 3.06 V
|   falling waveform, R_fixture 500, V_fixture 3.3: 20-80 % time 314ps typ, 431ps min, 245ps max; typ from 3.3 V to 0.19 V
|   rising waveform, R_fixture 500, V_fixture 3.3: 20-80 % time 423ps typ, 571ps min, 317ps max; typ from 0.19 V to 3.3 V
|   falling waveform, R_fixture 500, V_fixture 0: 20-80 % time 315ps typ, 424ps min, 247ps max; typ from 3.06 V to 0 V
[GND Clamp]
| ALVCH162260_BIO_33
|   Voltage   I(typ)   I(min)   I(max)
-3.3V     -546.5mA   -540mA     -557.6mA
-1.14V    -68.43mA   -75.37mA   -59.82mA
-1.1V     -60.25mA   -67.4mA    -51.31mA
-1.065V   -53.19mA   -60.52mA   -44.01mA
-920mV    -25.69mA   -33.22mA   -17.22mA
-875mV    -18.25mA   -25.42mA   -12.05mA
-815mV    -10.16mA   -15.93mA   -8.73mA
-765mV    -5.949mA   -9.317mA   -7.024mA
-710mV    -3.729mA   -4.199mA   -5.313mA
-595mV    -1.425mA   -518.9uA   -2.115mA
-385mV    -99.03uA   -79.81uA   -142.6uA
3.3V      116.8pA    41.6uA     -79.23uA
[POWER Clamp]
| ALVCH162260_BIO_33
|   Voltage   I(typ)   I(min)   I(max)
-3.3V     46.44mA    34.69mA    63.82mA
-1.595V   11.71mA    7.639mA    18.52mA
-1.565V   11.18mA    7.241mA    17.81mA
-1.335V   7.309mA    4.385mA    12.53mA
-1.205V   5.306mA    2.964mA    9.721mA
-1.09V    3.685mA    1.874mA    7.37mA
-955mV    2.031mA    882.6uA    4.813mA
-835mV    891.3uA    423.4uA    2.785mA
-740mV    343.9uA    325.8uA    1.406mA
-640mV    199.5uA    236.9uA    346uA
-570mV    143.4uA    179.1uA    166uA
-48.03fV  116.8pA    362.7pA    65.25pA
[Pulldown]
| ALVCH162260_BIO_33
|   Voltage   I(typ)   I(min)   I(max)
-3.3V     -39.7mA    -34.2mA    -47.28mA
-1.35V    -26.49mA   -23.22mA   -31.35mA
-795mV    -20.95mA   -18.12mA   -25.81mA
-510mV    -16.47mA   -13.15mA   -21.24mA
2.405V    76.63mA    59.76mA    99.8mA
3.465V    108.9mA    83.57mA    142.6mA
4.065V    126.2mA    94.28mA    166.4mA
4.245V    129.9mA    95.95mA    173.3mA
4.445V    133.1mA    97.18mA    178.6mA
5.12V     140.4mA    96.81mA    191mA
5.925V    144.5mA    86.08mA    201.1mA
6.6V      143.6mA    75.82mA    207.1mA
[Pullup]
| ALVCH162260_BIO_33
|   Voltage   I(typ)   I(min)   I(max)
-3.3V     37.94mA    30.77mA    46.43mA
-1.595V   28.91mA    23.75mA    34.59mA
-690mV    17.2mA     13.15mA    22.09mA
1.185V    -28.57mA   -21.42mA   -37.96mA
2.59V     -58.98mA   -42.21mA   -79.98mA
3.56V     -76.5mA    -50.72mA   -106.3mA
3.82V     -80.2mA    -48.67mA   -112.9mA
4.105V    -79.11mA   -44.96mA   -119.6mA
4.59V     -73.1mA    -37.49mA   -116.7mA
5.37V     -57.26mA   -25.2mA    -105.7mA
6.23V     -38.98mA   -22.13mA   -84.54mA
6.6V      -35.97mA   -21.63mA   -74.58mA
[Ramp]
| ALVCH162260_BIO_33
| variable   typ   min   max
dV/dt_r   1.84/4.40E-10   1.63/5.99E-10   2.04/3.29E-10
dV/dt_f   1.88/3.23E-10   1.68/4.42E-10   2.07/2.50E-10
R_load = 500
[Rising Waveform]
| ALVCH162260_BIO_33
R_fixture =   500
C_fixture =   0
L_fixture =   0
V_fixture =   0
V_fixture_min = 0
V_fixture_max = 0
|   Time   V(typ)   V(min)   V(max)
0s        495.2pV    1.396nV    369.6pV
2.44ns    -1.364mV   1.408mV    36.63mV
2.655ns   4.461mV    381uV      515.1mV
2.895ns   249mV      -4.279mV   2.22V
3.07ns    836.4mV    -5.989mV   2.901V
3.41ns    2.335V     142.1mV    3.286V
3.815ns   2.878V     1.035V     3.378V
4.41ns    3.034V     2.357V     3.392V
5.615ns   3.055V     2.7V       3.394V
50ns      3.055V     2.715V     3.394V
[Falling Waveform]
| ALVCH162260_BIO_33
R_fixture =   500
C_fixture =   0
L_fixture =   0
V_fixture =   3.3
V_fixture_min = 3
V_fixture_max = 3.6
|   Time   V(typ)   V(min)   V(max)
0s        3.3V       3V         3.6V
2.16ns    3.299V     3V         3.571V
2.295ns   3.298V     3V         3.113V
2.65ns    3.299V     2.998V     585.8mV
2.835ns   2.802V     2.998V     330.9mV
3.125ns   963.8mV    3.008V     217.5mV
3.425ns   395.4mV    2.98V      175.2mV
4.2ns     206.6mV    625.4mV    163mV
5.3ns     190.5mV    237.6mV    162.2mV
50ns      189.7mV    214.5mV    162.1mV
[Rising Waveform]
| ALVCH162260_BIO_33
R_fixture =   500
C_fixture =   0
L_fixture =   0
V_fixture =   3.3
V_fixture_min = 3
V_fixture_max = 3.6
|   Time   V(typ)   V(min)   V(max)
0s        189.7mV    214.5mV    162.1mV
2.44ns    187.9mV    215.7mV    200.3mV
2.645ns   191.6mV    214.3mV    659.2mV
2.89ns    448.5mV    209.5mV    2.423V
3.05ns    994mV      207.6mV    3.076V
3.385ns   2.548V     349.4mV    3.491V
3.79ns    3.13V      1.28V      3.584V
4.365ns   3.28V      2.641V     3.597V
5.505ns   3.299V     2.985V     3.6V
50ns      3.3V       3V         3.6V
[Falling Waveform]
| ALVCH162260_BIO_33
R_fixture =   500
C_fixture =   0
L_fixture =   0
V_fixture =   0
V_fixture_min = 0
V_fixture_max = 0
|   Time   V(typ)   V(min)   V(max)
0s        3.055V     2.715V     3.394V
2.155ns   3.055V     2.714V     3.369V
2.285ns   3.054V     2.714V     2.946V
2.65ns    3.052V     2.713V     416.3mV
2.815ns   2.616V     2.713V     184.1mV
3.11ns    781.7mV    2.723V     54.63mV
3.4ns     220mV      2.703V     12.75mV
4.17ns    15.7mV     403.3mV    825.7uV
5.25ns    691.1uV    20.24mV    138.1uV
50ns      920.7nV    1.369uV    541.5nV
